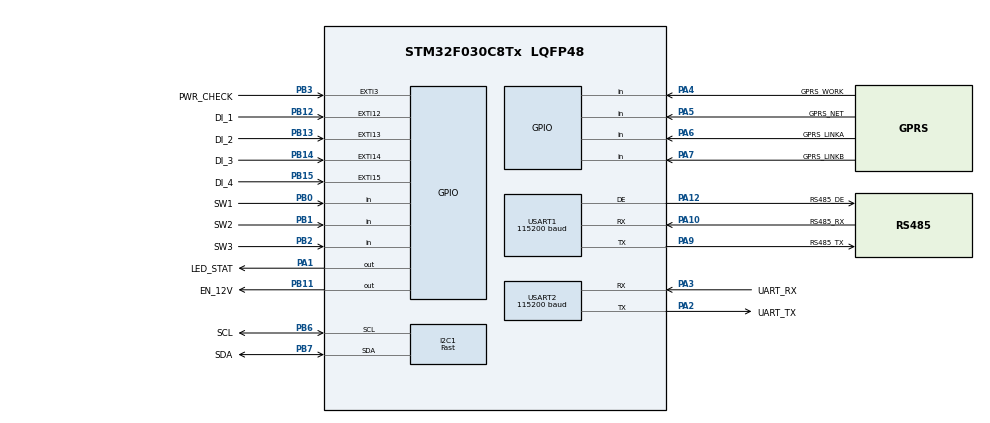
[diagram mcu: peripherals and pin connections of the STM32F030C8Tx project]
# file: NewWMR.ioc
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I2C1.I2C_Speed_Mode=I2C_Fast
I2C1.OwnAddress=0x78
I2C1.Speed=400
I2C1.Timing=0x0000020B
Mcu.Family=STM32F0
Mcu.Name=STM32F030C8Tx
Mcu.Package=LQFP48
NVIC.EXTI2_3_IRQn=true\:0\:0\:false\:false\:true\:true\:true
NVIC.EXTI4_15_IRQn=true\:0\:0\:false\:false\:true\:true\:true
NVIC.USART1_IRQn=true\:0\:0\:false\:false\:true\:true\:true
NVIC.USART2_IRQn=true\:0\:0\:false\:false\:true\:true\:true
PA1.GPIO_Label=LED_STAT
PA1.GPIO_PuPd=GPIO_PULLUP
PA1.Signal=GPIO_Output
PA10.GPIO_Label=RS485_RX
PA10.Mode=Asynchronous
PA10.Signal=USART1_RX
PA12.GPIO_Label=RS485_DE
PA12.Mode=Hardware Flow Control (RS485)
PA12.Signal=USART1_DE
PA13.Mode=Serial_Wire
PA13.Signal=SYS_SWDIO
PA14.Mode=Serial_Wire
PA14.Signal=SYS_SWCLK
PA2.GPIO_Label=UART_TX
PA2.Mode=Asynchronous
PA2.Signal=USART2_TX
PA3.GPIO_Label=UART_RX
PA3.Mode=Asynchronous
PA3.Signal=USART2_RX
PA4.GPIO_Label=GPRS_WORK
PA4.GPIO_PuPd=GPIO_NOPULL
PA4.Signal=GPIO_Input
PA5.GPIO_Label=GPRS_NET
PA5.GPIO_PuPd=GPIO_NOPULL
PA5.Signal=GPIO_Input
PA6.GPIO_Label=GPRS_LINKA
PA6.Signal=GPIO_Input
PA7.GPIO_Label=GPRS_LINKB
PA7.Signal=GPIO_Input
PA9.GPIO_Label=RS485_TX
PA9.Mode=Asynchronous
PA9.Signal=USART1_TX
PB0.GPIO_Label=SW1
PB0.Signal=GPIO_Input
PB1.GPIO_Label=SW2
PB1.Signal=GPIO_Input
PB11.GPIO_Label=EN_12V
PB11.GPIO_PuPd=GPIO_PULLUP
PB11.Signal=GPIO_Output
PB12.GPIO_Label=DI_1
PB12.GPIO_ModeDefaultEXTI=GPIO_MODE_IT_RISING
PB12.Signal=GPXTI12
PB13.GPIO_Label=DI_2
PB13.Signal=GPXTI13
PB14.GPIO_Label=DI_3
PB14.Signal=GPXTI14
PB15.GPIO_Label=DI_4
PB15.Signal=GPXTI15
PB2.GPIO_Label=SW3
PB2.Signal=GPIO_Input
PB3.GPIO_Label=PWR_CHECK
PB3.GPIO_ModeDefaultEXTI=GPIO_MODE_IT_FALLING
PB3.Signal=GPXTI3
PB6.GPIO_Label=SCL
PB6.Mode=I2C
PB6.Signal=I2C1_SCL
PB7.GPIO_Label=SDA
PB7.Mode=I2C
PB7.Signal=I2C1_SDA
ProjectManager.HeapSize=0x200
ProjectManager.StackSize=0x400
ProjectManager.TargetToolchain=Makefile
RCC.AHBFreq_Value=48000000
RCC.APB1Freq_Value=48000000
RCC.APB1TimFreq_Value=48000000
RCC.HCLKFreq_Value=48000000
RCC.PLLMUL=RCC_PLL_MUL12
RCC.SYSCLKFreq_VALUE=48000000
RCC.SYSCLKSource=RCC_SYSCLKSOURCE_PLLCLK
USART1.BaudRate=115200
USART1.VirtualMode-Asynchronous=VM_ASYNC
USART1.VirtualMode-Hardware\ Flow\ Control\ (RS485)=VM_ASYNC
USART1.WordLength=WORDLENGTH_8B
USART2.BaudRate=115200
USART2.VirtualMode-Asynchronous=VM_ASYNC
board=custom

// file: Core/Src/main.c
/* USER CODE BEGIN Header */
/**
 ******************************************************************************
 * @file           : main.c
 * @brief          : Main program body
 ******************************************************************************
 * @attention
 *
 * Copyright (c) 2022 STMicroelectronics.
 * All rights reserved.
 *
 * This software is licensed under terms that can be found in the LICENSE file
 * in the root directory of this software component.
 * If no LICENSE file comes with this software, it is provided AS-IS.
 *
 ******************************************************************************
 */
/* USER CODE END Header */
#include "main.h"
#include "i2c.h"
#include "usart.h"
#include "gpio.h"

/* USER CODE BEGIN Includes */
// #include <stdio.h>
#include <string.h>
#include "func.h"
#include "para.h"
#include "rs485.h"
#include "gprs_7gx.h"
/* USER CODE END Includes */

/* USER CODE BEGIN PM */
// #define h_rs485 huart1
// #define h_gprs huart2

/* USER CODE END PM */

/* USER CODE BEGIN PV */

SYS_MODE sys_mode;

uint8_t aRxBuffer;
uint8_t bRxBuffer;

PARA para;
FILTER filter;
CH_STATE ch_state[4];
CH_STATE pwr_check_state;
uint8_t pwr_check_filter;
/* USER CODE END PV */

void SystemClock_Config(void);

int main(void)
{
  /* USER CODE BEGIN 1 */
  uint32_t _timeout_100ms = 0, _timeout_1s = 0;

  /* USER CODE END 1 */

  /* MCU Configuration--------------------------------------------------------*/

  /* Reset of all peripherals, Initializes the Flash interface and the Systick. */
  HAL_Init();

  /* Configure the system clock */
  SystemClock_Config();

  /* Initialize all configured peripherals */
  MX_GPIO_Init();
  MX_I2C1_Init();
  MX_USART1_UART_Init();
  MX_USART2_UART_Init();
  /* USER CODE BEGIN 2 */

  // sys_mode = SystemModeSelect();
  sys_mode = SYS_MODE_INI;

  Para_Init();

  HAL_UART_Receive_IT(&h_rs485, (uint8_t *)&aRxBuffer, 1);
  HAL_UART_Receive_IT(&h_gprs, (uint8_t *)&bRxBuffer, 1);

  /* USER CODE END 2 */

  /* Infinite loop */
  while (1)
  {

    /* USER CODE BEGIN 3 */
    // 100ms
    if ((HAL_GetTick() - _timeout_100ms) >= 100)
    {
      _timeout_100ms = HAL_GetTick();

      Update_State();
    }

    // 1s
    if ((HAL_GetTick() - _timeout_1s) >= 1000)
    {
      _timeout_1s = HAL_GetTick();

      Run();

    }
  }
  /* USER CODE END 3 */
}

void SystemClock_Config(void)
{
  RCC_OscInitTypeDef RCC_OscInitStruct = {0};
  RCC_ClkInitTypeDef RCC_ClkInitStruct = {0};
  RCC_PeriphCLKInitTypeDef PeriphClkInit = {0};

  /** Initializes the RCC Oscillators according to the specified parameters
  * in the RCC_OscInitTypeDef structure.
  */
  RCC_OscInitStruct.OscillatorType = RCC_OSCILLATORTYPE_HSI;
  RCC_OscInitStruct.HSIState = RCC_HSI_ON;
  RCC_OscInitStruct.HSICalibrationValue = RCC_HSICALIBRATION_DEFAULT;
  RCC_OscInitStruct.PLL.PLLState = RCC_PLL_ON;
  RCC_OscInitStruct.PLL.PLLSource = RCC_PLLSOURCE_HSI;
  RCC_OscInitStruct.PLL.PLLMUL = RCC_PLL_MUL4;
  RCC_OscInitStruct.PLL.PREDIV = RCC_PREDIV_DIV1;
  if (HAL_RCC_OscConfig(&RCC_OscInitStruct) != HAL_OK)
  {
    Error_Handler();
  }
  /** Initializes the CPU, AHB and APB buses clocks
  */
  RCC_ClkInitStruct.ClockType = RCC_CLOCKTYPE_HCLK|RCC_CLOCKTYPE_SYSCLK
                              |RCC_CLOCKTYPE_PCLK1;
  RCC_ClkInitStruct.SYSCLKSource = RCC_SYSCLKSOURCE_PLLCLK;
  RCC_ClkInitStruct.AHBCLKDivider = RCC_SYSCLK_DIV2;
  RCC_ClkInitStruct.APB1CLKDivider = RCC_HCLK_DIV1;

  if (HAL_RCC_ClockConfig(&RCC_ClkInitStruct, FLASH_LATENCY_0) != HAL_OK)
  {
    Error_Handler();
  }
  PeriphClkInit.PeriphClockSelection = RCC_PERIPHCLK_USART1|RCC_PERIPHCLK_I2C1;
  PeriphClkInit.Usart1ClockSelection = RCC_USART1CLKSOURCE_PCLK1;
  PeriphClkInit.I2c1ClockSelection = RCC_I2C1CLKSOURCE_HSI;
  if (HAL_RCCEx_PeriphCLKConfig(&PeriphClkInit) != HAL_OK)
  {
    Error_Handler();
  }
}

/* USER CODE BEGIN 4 */

void HAL_GPIO_EXTI_Callback(uint16_t GPIO_Pin)
{
  UNUSED(GPIO_Pin);

  if (GPIO_Pin == PWR_CHECK_Pin)
  {
    if (pwr_check_state == READY)
    {
      pwr_check_state = TRIGGED;
      UserWrite();
      HAL_UART_Transmit(&h_rs485, (uint8_t *)"PWR_TRIGGED\r", 12, 0xffff);
      // exit_trig_state = PWR_TRIGGED;
    }
  }
  else if (GPIO_Pin == DI_3_Pin)
  {

    if (ch_state[CH1] == READY)
    {
      ch_state[CH1] = TRIGGED;
      HAL_UART_Transmit(&h_rs485, (uint8_t *)"DI1_TRIGGED\r", 12, 0xffff);
    }
    // exit_trig_state = DI1_TRIGGED;
  }
  else if (GPIO_Pin == DI_4_Pin)
  {
    if (ch_state[CH2] == READY)
    {
      ch_state[CH2] = TRIGGED;
      HAL_UART_Transmit(&h_rs485, (uint8_t *)"DI2_TRIGGED\r", 12, 0xffff);
    }
    // exit_trig_state = DI2_TRIGGED;
  }
  else if (GPIO_Pin == DI_1_Pin)
  {
    if (ch_state[CH3] == READY)
    {
      ch_state[CH3] = TRIGGED;
      HAL_UART_Transmit(&h_rs485, (uint8_t *)"DI3_TRIGGED\r", 12, 0xffff);
    }
  }
  else if (GPIO_Pin == DI_2_Pin)
  {
    if (ch_state[CH4] == READY)
    {
      ch_state[CH4] = TRIGGED;
      HAL_UART_Transmit(&h_rs485, (uint8_t *)"DI4_TRIGGED\r", 12, 0xffff);
    }
  }
}

void HAL_UART_RxCpltCallback(UART_HandleTypeDef *huart)
{
  /* Prevent unused argument(s) compilation warning */
  UNUSED(huart);
  /* NOTE : This function should not be modified, when the callback is needed,
            the HAL_UART_RxCpltCallback can be implemented in the user file
   */

  if(huart == &h_rs485) {

    RS485_Receiver();

    HAL_UART_Receive_IT(&h_rs485, (uint8_t *)&aRxBuffer, 1);

  }else if( huart == &h_gprs){

    gprsReceiver();

    HAL_UART_Receive_IT(&h_gprs, (uint8_t *)&bRxBuffer, 1);
  }
}

/* USER CODE END 4 */

void Error_Handler(void)
{
  __disable_irq();
  while (1)
  {
  }
}
